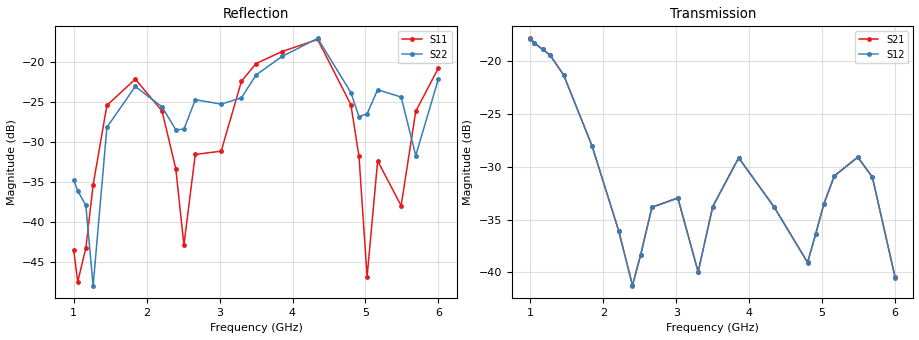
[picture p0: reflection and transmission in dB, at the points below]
!Agilent Technologies,E8364B,MY43040528,A.07.50.67
!Agilent E8364B: A.07.50.67
!Date: Sunday, March 01, 2026 21:34:27
!Correction: S11(Full 2 Port(1,2))
!S21(Full 2 Port(1,2))
!S12(Full 2 Port(1,2))
!S22(Full 2 Port(1,2))
!S2P File: Measurements: S11, S21, S12, S22:
# Hz S  dB  R 50
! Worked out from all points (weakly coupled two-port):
!   451 points, 1 GHz to 6 GHz, reference 50 ohm
!   highest |S21| = -17.88 dB at 1 GHz (marker M1); lowest = -41.2 dB at 2.4 GHz (marker M2)
!   lowest |S11| = -47.4 dB at 1.056 GHz (marker M3), VSWR 1.01, Z = 49.9 + j0.41 ohm
!   |S11| at or under -10 dB: start of sweep to end of sweep
!   |S22| runs from -48.0 to -16.6 dB; largest |S21 - S12| = 0.00046
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1e9  -43.45 54.7  -17.88 26.0  -17.91 26.1  -34.73 13.6
1.055556e9  -47.43 105.0  -18.30 9.5  -18.33 9.6  -36.08 14.5
1.166667e9  -43.21 164.3  -18.91 -23.9  -18.93 -23.9  -37.89 14.7
1.266667e9  -35.34 -166.9  -19.42 -56.5  -19.45 -56.5  -47.91 79.9
1.455556e9  -25.42 167.2  -21.32 -121.0  -21.34 -121.0  -28.15 90.9
1.844444e9  -22.14 93.6  -28.01 114.8  -28.03 114.9  -23.06 -1.1
2.211111e9  -26.12 43.6  -36.06 -7.0  -36.08 -6.9  -25.61 -53.7
2.4e9  -33.33 19.6  -41.21 -129.2  -41.25 -129.2  -28.45 -63.8
2.511111e9  -42.86 70.2  -38.34 144.7  -38.38 144.8  -28.39 -52.0
2.666667e9  -31.54 108.7  -33.83 62.7  -33.86 62.8  -24.72 -57.7
3.022222e9  -31.13 95.6  -32.95 -83.9  -32.98 -83.8  -25.26 -114.2
3.3e9  -22.40 93.6  -39.93 -135.6  -39.96 -135.7  -24.47 -100.6
3.5e9  -20.20 63.1  -33.77 -158.8  -33.80 -158.7  -21.62 -124.6
3.855556e9  -18.70 29.1  -29.15 70.3  -29.18 70.3  -19.32 -157.2
4.344444e9  -17.20 -46.5  -33.83 -110.7  -33.86 -110.7  -17.06 113.6
4.8e9  -25.34 -135.1  -39.04 20.4  -39.07 20.4  -23.82 32.0
4.911111e9  -31.79 -163.6  -36.37 -47.4  -36.40 -47.3  -26.83 30.4
5.022222e9  -46.79 79.3  -33.54 -105.2  -33.57 -105.2  -26.48 40.4
5.166667e9  -32.34 -23.5  -30.86 -172.7  -30.90 -172.7  -23.47 27.7
5.488889e9  -37.94 -33.4  -29.09 46.0  -29.12 46.0  -24.38 -41.5
5.688889e9  -26.16 -11.7  -30.99 -38.8  -31.02 -38.8  -31.69 -29.2
6e9  -20.76 -70.1  -40.45 -150.1  -40.48 -150.1  -22.11 -27.4
